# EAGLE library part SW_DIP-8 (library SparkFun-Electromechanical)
DIP Switch 8 Position Spark Fun Electronics SKU : COM-08034

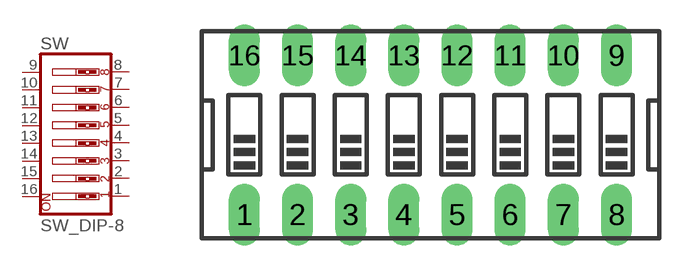
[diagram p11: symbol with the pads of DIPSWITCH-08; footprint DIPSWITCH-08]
Designator prefix SW

## SW_DIP-8  [DIPSWITCH-08]
1  1  pas
2  2  pas
3  3  pas
4  4  pas
5  5  pas
6  6  pas
7  7  pas
8  8  pas
9  9  pas
10  10  pas
11  11  pas
12  12  pas
13  13  pas
14  14  pas
15  15  pas
16  16  pas

## Footprint DIPSWITCH-08 (pad centres in mm)
DIP SWITCH
drill 0.97 long: 1 -8.89,-3.81; 2 -6.35,-3.81; 3 -3.81,-3.81; 4 -1.27,-3.81; 5 1.27,-3.81; 6 3.81,-3.81; 7 6.35,-3.81; 8 8.89,-3.81; 9 8.89,3.81; 10 6.35,3.81; 11 3.81,3.81; 12 1.27,3.81; 13 -1.27,3.81; 14 -3.81,3.81; 15 -6.35,3.81; 16 -8.89,3.81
